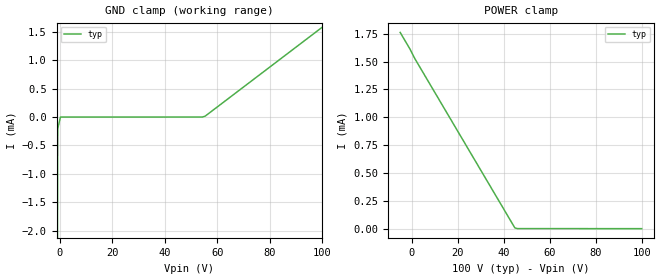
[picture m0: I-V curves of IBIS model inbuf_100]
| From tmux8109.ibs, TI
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| inbuf_100
[Model]   inbuf_100
Model_type   Input
Vinl = 1.3
Vinh = 0.8
|   typ   min   max
C_comp   1.598234e-13   NA   NA
[Voltage Range]   100   NA   NA
[Temperature Range]   27   NA   NA
[Power Clamp Reference]   100   NA   NA
[GND Clamp Reference]   0   NA   NA
[GND Clamp]
|   Voltage   I(typ)   I(min)   I(max)
-5V       -116.5mA   NA         NA
-1.818V   -26.13mA   NA         NA
-757.6mV  -207.5uA   NA         NA
303mV     62.34nA    NA         NA
54.39V    555.2nA    NA         NA
55.45V    16.93uA    NA         NA
100V      1.582mA    NA         NA
[POWER Clamp]
|   Voltage   I(typ)   I(min)   I(max)
-5V       1.762mA    NA         NA
-758mV    1.613mA    NA         NA
1.364V    1.527mA    NA         NA
44.85V    7.413uA    NA         NA
45.91V    555.2nA    NA         NA
100V      -220pA     NA         NA
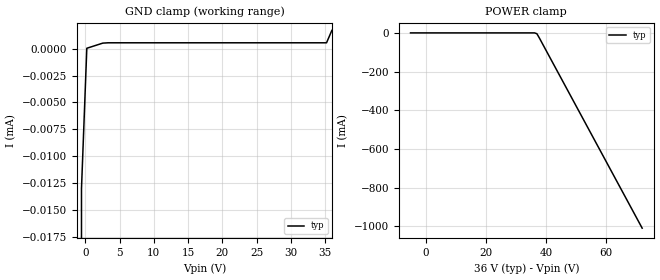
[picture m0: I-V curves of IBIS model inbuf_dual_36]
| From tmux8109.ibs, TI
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| inbuf_dual_36
[Model]   inbuf_dual_36
Model_type   Input
Vinl = 1.3
Vinh = 0.8
|   typ   min   max
C_comp   4.014581e-13   NA   NA
[Voltage Range]   36   NA   NA
[Temperature Range]   27   NA   NA
[Power Clamp Reference]   36   NA   NA
[GND Clamp Reference]   0   NA   NA
[GND Clamp]
|   Voltage   I(typ)   I(min)   I(max)
-41V      -1.153A    NA         NA
-1.333V   -12.84mA   NA         NA
-555.6mV  -13.03uA   NA         NA
222.2mV   45.73nA    NA         NA
2.556V    525.1nA    NA         NA
3.333V    554.7nA    NA         NA
35.22V    555.1nA    NA         NA
36V       1.709uA    NA         NA
[POWER Clamp]
|   Voltage   I(typ)   I(min)   I(max)
-5V       2.169uA    NA         NA
36.22V    -48.44nA   NA         NA
37V       -4.233mA   NA         NA
37.78V    -25.01mA   NA         NA
72V       -1.009A    NA         NA
